VERSION 5.8 ;
BUSBITCHARS "[]" ;
DIVIDERCHAR "/" ;
UNITS
    DATABASE MICRONS 1000 ;
END UNITS

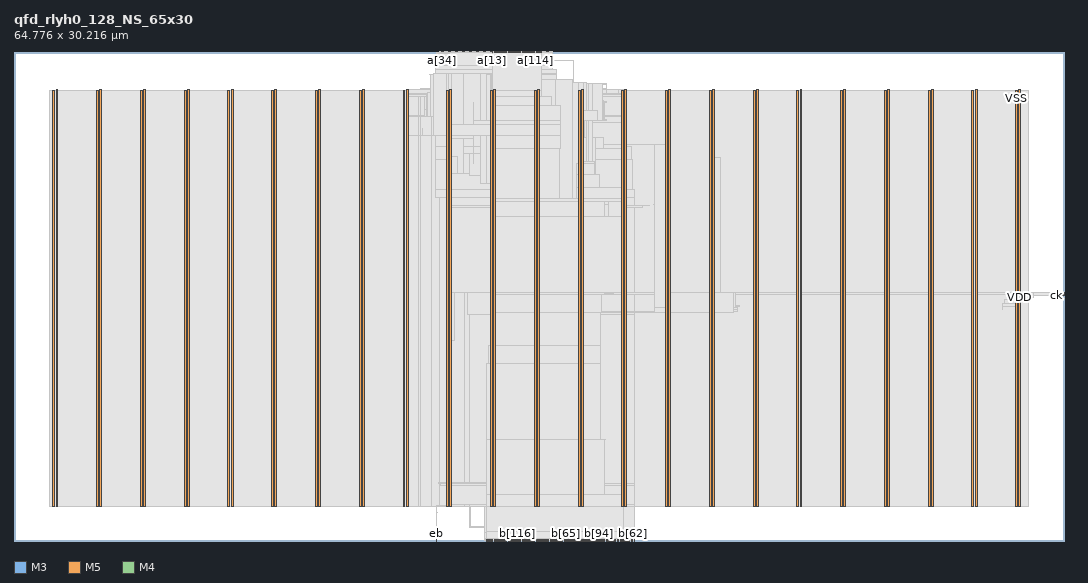
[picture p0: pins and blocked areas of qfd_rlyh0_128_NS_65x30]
MACRO qfd_rlyh0_128_NS_65x30
  FOREIGN qfd_rlyh0_128_NS_65x30 0 0 ;
  CLASS BLOCK ;
  SIZE 64.776 BY 30.216 ;
  PIN a[0]
    DIRECTION INPUT ;
    USE SIGNAL ;
    PORT
      LAYER M3 ;
        RECT  28.548 30.179 28.566 30.216 ;
    END
  END a[0]
  PIN a[100]
    DIRECTION INPUT ;
    USE SIGNAL ;
    PORT
      LAYER M3 ;
        RECT  31.14 30.179 31.158 30.216 ;
    END
  END a[100]
  PIN a[101]
    DIRECTION INPUT ;
    USE SIGNAL ;
    PORT
      LAYER M3 ;
        RECT  31.212 30.179 31.23 30.216 ;
    END
  END a[101]
  PIN a[102]
    DIRECTION INPUT ;
    USE SIGNAL ;
    PORT
      LAYER M3 ;
        RECT  31.284 30.179 31.302 30.216 ;
    END
  END a[102]
  PIN a[103]
    DIRECTION INPUT ;
    USE SIGNAL ;
    PORT
      LAYER M3 ;
        RECT  31.356 30.179 31.374 30.216 ;
    END
  END a[103]
  PIN a[104]
    DIRECTION INPUT ;
    USE SIGNAL ;
    PORT
      LAYER M3 ;
        RECT  31.428 30.179 31.446 30.216 ;
    END
  END a[104]
  PIN a[105]
    DIRECTION INPUT ;
    USE SIGNAL ;
    PORT
      LAYER M3 ;
        RECT  31.5 30.179 31.518 30.216 ;
    END
  END a[105]
  PIN a[106]
    DIRECTION INPUT ;
    USE SIGNAL ;
    PORT
      LAYER M3 ;
        RECT  31.572 30.179 31.59 30.216 ;
    END
  END a[106]
  PIN a[107]
    DIRECTION INPUT ;
    USE SIGNAL ;
    PORT
      LAYER M3 ;
        RECT  31.644 30.179 31.662 30.216 ;
    END
  END a[107]
  PIN a[108]
    DIRECTION INPUT ;
    USE SIGNAL ;
    PORT
      LAYER M3 ;
        RECT  31.716 30.179 31.734 30.216 ;
    END
  END a[108]
  PIN a[109]
    DIRECTION INPUT ;
    USE SIGNAL ;
    PORT
      LAYER M3 ;
        RECT  31.788 30.179 31.806 30.216 ;
    END
  END a[109]
  PIN a[10]
    DIRECTION INPUT ;
    USE SIGNAL ;
    PORT
      LAYER M3 ;
        RECT  29.268 30.179 29.286 30.216 ;
    END
  END a[10]
  PIN a[110]
    DIRECTION INPUT ;
    USE SIGNAL ;
    PORT
      LAYER M3 ;
        RECT  31.86 30.179 31.878 30.216 ;
    END
  END a[110]
  PIN a[111]
    DIRECTION INPUT ;
    USE SIGNAL ;
    PORT
      LAYER M3 ;
        RECT  31.932 30.179 31.95 30.216 ;
    END
  END a[111]
  PIN a[112]
    DIRECTION INPUT ;
    USE SIGNAL ;
    PORT
      LAYER M3 ;
        RECT  32.004 30.179 32.022 30.216 ;
    END
  END a[112]
  PIN a[113]
    DIRECTION INPUT ;
    USE SIGNAL ;
    PORT
      LAYER M3 ;
        RECT  32.076 30.179 32.094 30.216 ;
    END
  END a[113]
  PIN a[114]
    DIRECTION INPUT ;
    USE SIGNAL ;
    PORT
      LAYER M3 ;
        RECT  32.148 30.179 32.166 30.216 ;
    END
  END a[114]
  PIN a[115]
    DIRECTION INPUT ;
    USE SIGNAL ;
    PORT
      LAYER M3 ;
        RECT  32.22 30.179 32.238 30.216 ;
    END
  END a[115]
  PIN a[116]
    DIRECTION INPUT ;
    USE SIGNAL ;
    PORT
      LAYER M3 ;
        RECT  32.292 30.179 32.31 30.216 ;
    END
  END a[116]
  PIN a[117]
    DIRECTION INPUT ;
    USE SIGNAL ;
    PORT
      LAYER M3 ;
        RECT  32.364 30.179 32.382 30.216 ;
    END
  END a[117]
  PIN a[118]
    DIRECTION INPUT ;
    USE SIGNAL ;
    PORT
      LAYER M3 ;
        RECT  32.436 30.179 32.454 30.216 ;
    END
  END a[118]
  PIN a[119]
    DIRECTION INPUT ;
    USE SIGNAL ;
    PORT
      LAYER M3 ;
        RECT  32.508 30.179 32.526 30.216 ;
    END
  END a[119]
  PIN a[11]
    DIRECTION INPUT ;
    USE SIGNAL ;
    PORT
      LAYER M3 ;
        RECT  29.34 30.179 29.358 30.216 ;
    END
  END a[11]
  PIN a[120]
    DIRECTION INPUT ;
    USE SIGNAL ;
    PORT
      LAYER M3 ;
        RECT  32.58 30.179 32.598 30.216 ;
    END
  END a[120]
  PIN a[121]
    DIRECTION INPUT ;
    USE SIGNAL ;
    PORT
      LAYER M3 ;
        RECT  32.652 30.179 32.67 30.216 ;
    END
  END a[121]
  PIN a[122]
    DIRECTION INPUT ;
    USE SIGNAL ;
    PORT
      LAYER M3 ;
        RECT  32.724 30.179 32.742 30.216 ;
    END
  END a[122]
  PIN a[123]
    DIRECTION INPUT ;
    USE SIGNAL ;
    PORT
      LAYER M3 ;
        RECT  32.796 30.179 32.814 30.216 ;
    END
  END a[123]
  PIN a[124]
    DIRECTION INPUT ;
    USE SIGNAL ;
    PORT
      LAYER M3 ;
        RECT  32.868 30.179 32.886 30.216 ;
    END
  END a[124]
  PIN a[125]
    DIRECTION INPUT ;
    USE SIGNAL ;
    PORT
      LAYER M3 ;
        RECT  32.94 30.179 32.958 30.216 ;
    END
  END a[125]
  PIN a[126]
    DIRECTION INPUT ;
    USE SIGNAL ;
    PORT
      LAYER M3 ;
        RECT  33.012 30.179 33.03 30.216 ;
    END
  END a[126]
  PIN a[127]
    DIRECTION INPUT ;
    USE SIGNAL ;
    PORT
      LAYER M3 ;
        RECT  33.084 30.179 33.102 30.216 ;
    END
  END a[127]
  PIN a[12]
    DIRECTION INPUT ;
    USE SIGNAL ;
    PORT
      LAYER M3 ;
        RECT  29.412 30.179 29.43 30.216 ;
    END
  END a[12]
  PIN a[13]
    DIRECTION INPUT ;
    USE SIGNAL ;
    PORT
      LAYER M3 ;
        RECT  29.484 30.179 29.502 30.216 ;
    END
  END a[13]
  PIN a[14]
    DIRECTION INPUT ;
    USE SIGNAL ;
    PORT
      LAYER M3 ;
        RECT  29.556 30.179 29.574 30.216 ;
    END
  END a[14]
  PIN a[15]
    DIRECTION INPUT ;
    USE SIGNAL ;
    PORT
      LAYER M3 ;
        RECT  29.628 30.179 29.646 30.216 ;
    END
  END a[15]
  PIN a[16]
    DIRECTION INPUT ;
    USE SIGNAL ;
    PORT
      LAYER M3 ;
        RECT  29.7 30.179 29.718 30.216 ;
    END
  END a[16]
  PIN a[17]
    DIRECTION INPUT ;
    USE SIGNAL ;
    PORT
      LAYER M3 ;
        RECT  29.772 30.179 29.79 30.216 ;
    END
  END a[17]
  PIN a[18]
    DIRECTION INPUT ;
    USE SIGNAL ;
    PORT
      LAYER M3 ;
        RECT  29.844 30.179 29.862 30.216 ;
    END
  END a[18]
  PIN a[19]
    DIRECTION INPUT ;
    USE SIGNAL ;
    PORT
      LAYER M3 ;
        RECT  29.916 30.179 29.934 30.216 ;
    END
  END a[19]
  PIN a[1]
    DIRECTION INPUT ;
    USE SIGNAL ;
    PORT
      LAYER M3 ;
        RECT  28.62 30.179 28.638 30.216 ;
    END
  END a[1]
  PIN a[20]
    DIRECTION INPUT ;
    USE SIGNAL ;
    PORT
      LAYER M3 ;
        RECT  29.988 30.179 30.006 30.216 ;
    END
  END a[20]
  PIN a[21]
    DIRECTION INPUT ;
    USE SIGNAL ;
    PORT
      LAYER M3 ;
        RECT  30.06 30.179 30.078 30.216 ;
    END
  END a[21]
  PIN a[22]
    DIRECTION INPUT ;
    USE SIGNAL ;
    PORT
      LAYER M3 ;
        RECT  30.132 30.179 30.15 30.216 ;
    END
  END a[22]
  PIN a[23]
    DIRECTION INPUT ;
    USE SIGNAL ;
    PORT
      LAYER M3 ;
        RECT  30.204 30.179 30.222 30.216 ;
    END
  END a[23]
  PIN a[24]
    DIRECTION INPUT ;
    USE SIGNAL ;
    PORT
      LAYER M3 ;
        RECT  30.276 30.179 30.294 30.216 ;
    END
  END a[24]
  PIN a[25]
    DIRECTION INPUT ;
    USE SIGNAL ;
    PORT
      LAYER M3 ;
        RECT  30.348 30.179 30.366 30.216 ;
    END
  END a[25]
  PIN a[26]
    DIRECTION INPUT ;
    USE SIGNAL ;
    PORT
      LAYER M3 ;
        RECT  30.42 30.179 30.438 30.216 ;
    END
  END a[26]
  PIN a[27]
    DIRECTION INPUT ;
    USE SIGNAL ;
    PORT
      LAYER M3 ;
        RECT  30.492 30.179 30.51 30.216 ;
    END
  END a[27]
  PIN a[28]
    DIRECTION INPUT ;
    USE SIGNAL ;
    PORT
      LAYER M3 ;
        RECT  30.564 30.179 30.582 30.216 ;
    END
  END a[28]
  PIN a[29]
    DIRECTION INPUT ;
    USE SIGNAL ;
    PORT
      LAYER M3 ;
        RECT  30.636 30.179 30.654 30.216 ;
    END
  END a[29]
  PIN a[2]
    DIRECTION INPUT ;
    USE SIGNAL ;
    PORT
      LAYER M3 ;
        RECT  28.692 30.179 28.71 30.216 ;
    END
  END a[2]
  PIN a[30]
    DIRECTION INPUT ;
    USE SIGNAL ;
    PORT
      LAYER M3 ;
        RECT  30.708 30.179 30.726 30.216 ;
    END
  END a[30]
  PIN a[31]
    DIRECTION INPUT ;
    USE SIGNAL ;
    PORT
      LAYER M3 ;
        RECT  30.78 30.179 30.798 30.216 ;
    END
  END a[31]
  PIN a[32]
    DIRECTION INPUT ;
    USE SIGNAL ;
    PORT
      LAYER M3 ;
        RECT  26.244 30.179 26.262 30.216 ;
    END
  END a[32]
  PIN a[33]
    DIRECTION INPUT ;
    USE SIGNAL ;
    PORT
      LAYER M3 ;
        RECT  26.316 30.179 26.334 30.216 ;
    END
  END a[33]
  PIN a[34]
    DIRECTION INPUT ;
    USE SIGNAL ;
    PORT
      LAYER M3 ;
        RECT  26.388 30.179 26.406 30.216 ;
    END
  END a[34]
  PIN a[35]
    DIRECTION INPUT ;
    USE SIGNAL ;
    PORT
      LAYER M3 ;
        RECT  26.46 30.179 26.478 30.216 ;
    END
  END a[35]
  PIN a[36]
    DIRECTION INPUT ;
    USE SIGNAL ;
    PORT
      LAYER M3 ;
        RECT  26.532 30.179 26.55 30.216 ;
    END
  END a[36]
  PIN a[37]
    DIRECTION INPUT ;
    USE SIGNAL ;
    PORT
      LAYER M3 ;
        RECT  26.604 30.179 26.622 30.216 ;
    END
  END a[37]
  PIN a[38]
    DIRECTION INPUT ;
    USE SIGNAL ;
    PORT
      LAYER M3 ;
        RECT  26.676 30.179 26.694 30.216 ;
    END
  END a[38]
  PIN a[39]
    DIRECTION INPUT ;
    USE SIGNAL ;
    PORT
      LAYER M3 ;
        RECT  26.748 30.179 26.766 30.216 ;
    END
  END a[39]
  PIN a[3]
    DIRECTION INPUT ;
    USE SIGNAL ;
    PORT
      LAYER M3 ;
        RECT  28.764 30.179 28.782 30.216 ;
    END
  END a[3]
  PIN a[40]
    DIRECTION INPUT ;
    USE SIGNAL ;
    PORT
      LAYER M3 ;
        RECT  26.82 30.179 26.838 30.216 ;
    END
  END a[40]
  PIN a[41]
    DIRECTION INPUT ;
    USE SIGNAL ;
    PORT
      LAYER M3 ;
        RECT  26.892 30.179 26.91 30.216 ;
    END
  END a[41]
  PIN a[42]
    DIRECTION INPUT ;
    USE SIGNAL ;
    PORT
      LAYER M3 ;
        RECT  26.964 30.179 26.982 30.216 ;
    END
  END a[42]
  PIN a[43]
    DIRECTION INPUT ;
    USE SIGNAL ;
    PORT
      LAYER M3 ;
        RECT  27.036 30.179 27.054 30.216 ;
    END
  END a[43]
  PIN a[44]
    DIRECTION INPUT ;
    USE SIGNAL ;
    PORT
      LAYER M3 ;
        RECT  27.108 30.179 27.126 30.216 ;
    END
  END a[44]
  PIN a[45]
    DIRECTION INPUT ;
    USE SIGNAL ;
    PORT
      LAYER M3 ;
        RECT  27.18 30.179 27.198 30.216 ;
    END
  END a[45]
  PIN a[46]
    DIRECTION INPUT ;
    USE SIGNAL ;
    PORT
      LAYER M3 ;
        RECT  27.252 30.179 27.27 30.216 ;
    END
  END a[46]
  PIN a[47]
    DIRECTION INPUT ;
    USE SIGNAL ;
    PORT
      LAYER M3 ;
        RECT  27.324 30.179 27.342 30.216 ;
    END
  END a[47]
  PIN a[48]
    DIRECTION INPUT ;
    USE SIGNAL ;
    PORT
      LAYER M3 ;
        RECT  27.396 30.179 27.414 30.216 ;
    END
  END a[48]
  PIN a[49]
    DIRECTION INPUT ;
    USE SIGNAL ;
    PORT
      LAYER M3 ;
        RECT  27.468 30.179 27.486 30.216 ;
    END
  END a[49]
  PIN a[4]
    DIRECTION INPUT ;
    USE SIGNAL ;
    PORT
      LAYER M3 ;
        RECT  28.836 30.179 28.854 30.216 ;
    END
  END a[4]
  PIN a[50]
    DIRECTION INPUT ;
    USE SIGNAL ;
    PORT
      LAYER M3 ;
        RECT  27.54 30.179 27.558 30.216 ;
    END
  END a[50]
  PIN a[51]
    DIRECTION INPUT ;
    USE SIGNAL ;
    PORT
      LAYER M3 ;
        RECT  27.612 30.179 27.63 30.216 ;
    END
  END a[51]
  PIN a[52]
    DIRECTION INPUT ;
    USE SIGNAL ;
    PORT
      LAYER M3 ;
        RECT  27.684 30.179 27.702 30.216 ;
    END
  END a[52]
  PIN a[53]
    DIRECTION INPUT ;
    USE SIGNAL ;
    PORT
      LAYER M3 ;
        RECT  27.756 30.179 27.774 30.216 ;
    END
  END a[53]
  PIN a[54]
    DIRECTION INPUT ;
    USE SIGNAL ;
    PORT
      LAYER M3 ;
        RECT  27.828 30.179 27.846 30.216 ;
    END
  END a[54]
  PIN a[55]
    DIRECTION INPUT ;
    USE SIGNAL ;
    PORT
      LAYER M3 ;
        RECT  27.9 30.179 27.918 30.216 ;
    END
  END a[55]
  PIN a[56]
    DIRECTION INPUT ;
    USE SIGNAL ;
    PORT
      LAYER M3 ;
        RECT  27.972 30.179 27.99 30.216 ;
    END
  END a[56]
  PIN a[57]
    DIRECTION INPUT ;
    USE SIGNAL ;
    PORT
      LAYER M3 ;
        RECT  28.044 30.179 28.062 30.216 ;
    END
  END a[57]
  PIN a[58]
    DIRECTION INPUT ;
    USE SIGNAL ;
    PORT
      LAYER M3 ;
        RECT  28.116 30.179 28.134 30.216 ;
    END
  END a[58]
  PIN a[59]
    DIRECTION INPUT ;
    USE SIGNAL ;
    PORT
      LAYER M3 ;
        RECT  28.188 30.179 28.206 30.216 ;
    END
  END a[59]
  PIN a[5]
    DIRECTION INPUT ;
    USE SIGNAL ;
    PORT
      LAYER M3 ;
        RECT  28.908 30.179 28.926 30.216 ;
    END
  END a[5]
  PIN a[60]
    DIRECTION INPUT ;
    USE SIGNAL ;
    PORT
      LAYER M3 ;
        RECT  28.26 30.179 28.278 30.216 ;
    END
  END a[60]
  PIN a[61]
    DIRECTION INPUT ;
    USE SIGNAL ;
    PORT
      LAYER M3 ;
        RECT  28.332 30.179 28.35 30.216 ;
    END
  END a[61]
  PIN a[62]
    DIRECTION INPUT ;
    USE SIGNAL ;
    PORT
      LAYER M3 ;
        RECT  28.404 30.179 28.422 30.216 ;
    END
  END a[62]
  PIN a[63]
    DIRECTION INPUT ;
    USE SIGNAL ;
    PORT
      LAYER M3 ;
        RECT  28.476 30.179 28.494 30.216 ;
    END
  END a[63]
  PIN a[64]
    DIRECTION INPUT ;
    USE SIGNAL ;
    PORT
      LAYER M5 ;
        RECT  29.52 30.132 29.544 30.216 ;
    END
  END a[64]
  PIN a[65]
    DIRECTION INPUT ;
    USE SIGNAL ;
    PORT
      LAYER M5 ;
        RECT  29.616 30.132 29.64 30.216 ;
    END
  END a[65]
  PIN a[66]
    DIRECTION INPUT ;
    USE SIGNAL ;
    PORT
      LAYER M5 ;
        RECT  29.712 30.132 29.736 30.216 ;
    END
  END a[66]
  PIN a[67]
    DIRECTION INPUT ;
    USE SIGNAL ;
    PORT
      LAYER M5 ;
        RECT  29.808 30.132 29.832 30.216 ;
    END
  END a[67]
  PIN a[68]
    DIRECTION INPUT ;
    USE SIGNAL ;
    PORT
      LAYER M5 ;
        RECT  29.904 30.132 29.928 30.216 ;
    END
  END a[68]
  PIN a[69]
    DIRECTION INPUT ;
    USE SIGNAL ;
    PORT
      LAYER M5 ;
        RECT  30 30.132 30.024 30.216 ;
    END
  END a[69]
  PIN a[6]
    DIRECTION INPUT ;
    USE SIGNAL ;
    PORT
      LAYER M3 ;
        RECT  28.98 30.179 28.998 30.216 ;
    END
  END a[6]
  PIN a[70]
    DIRECTION INPUT ;
    USE SIGNAL ;
    PORT
      LAYER M5 ;
        RECT  30.096 30.132 30.12 30.216 ;
    END
  END a[70]
  PIN a[71]
    DIRECTION INPUT ;
    USE SIGNAL ;
    PORT
      LAYER M5 ;
        RECT  30.192 30.132 30.216 30.216 ;
    END
  END a[71]
  PIN a[72]
    DIRECTION INPUT ;
    USE SIGNAL ;
    PORT
      LAYER M5 ;
        RECT  30.288 30.132 30.312 30.216 ;
    END
  END a[72]
  PIN a[73]
    DIRECTION INPUT ;
    USE SIGNAL ;
    PORT
      LAYER M5 ;
        RECT  30.384 30.132 30.408 30.216 ;
    END
  END a[73]
  PIN a[74]
    DIRECTION INPUT ;
    USE SIGNAL ;
    PORT
      LAYER M5 ;
        RECT  30.48 30.132 30.504 30.216 ;
    END
  END a[74]
  PIN a[75]
    DIRECTION INPUT ;
    USE SIGNAL ;
    PORT
      LAYER M5 ;
        RECT  30.576 30.132 30.6 30.216 ;
    END
  END a[75]
  PIN a[76]
    DIRECTION INPUT ;
    USE SIGNAL ;
    PORT
      LAYER M5 ;
        RECT  30.672 30.132 30.696 30.216 ;
    END
  END a[76]
  PIN a[77]
    DIRECTION INPUT ;
    USE SIGNAL ;
    PORT
      LAYER M5 ;
        RECT  30.768 30.132 30.792 30.216 ;
    END
  END a[77]
  PIN a[78]
    DIRECTION INPUT ;
    USE SIGNAL ;
    PORT
      LAYER M5 ;
        RECT  30.864 30.132 30.888 30.216 ;
    END
  END a[78]
  PIN a[79]
    DIRECTION INPUT ;
    USE SIGNAL ;
    PORT
      LAYER M5 ;
        RECT  30.96 30.132 30.984 30.216 ;
    END
  END a[79]
  PIN a[7]
    DIRECTION INPUT ;
    USE SIGNAL ;
    PORT
      LAYER M3 ;
        RECT  29.052 30.179 29.07 30.216 ;
    END
  END a[7]
  PIN a[80]
    DIRECTION INPUT ;
    USE SIGNAL ;
    PORT
      LAYER M5 ;
        RECT  31.056 30.132 31.08 30.216 ;
    END
  END a[80]
  PIN a[81]
    DIRECTION INPUT ;
    USE SIGNAL ;
    PORT
      LAYER M5 ;
        RECT  31.152 30.132 31.176 30.216 ;
    END
  END a[81]
  PIN a[82]
    DIRECTION INPUT ;
    USE SIGNAL ;
    PORT
      LAYER M5 ;
        RECT  31.248 30.132 31.272 30.216 ;
    END
  END a[82]
  PIN a[83]
    DIRECTION INPUT ;
    USE SIGNAL ;
    PORT
      LAYER M5 ;
        RECT  31.344 30.132 31.368 30.216 ;
    END
  END a[83]
  PIN a[84]
    DIRECTION INPUT ;
    USE SIGNAL ;
    PORT
      LAYER M5 ;
        RECT  31.44 30.132 31.464 30.216 ;
    END
  END a[84]
  PIN a[85]
    DIRECTION INPUT ;
    USE SIGNAL ;
    PORT
      LAYER M5 ;
        RECT  31.536 30.132 31.56 30.216 ;
    END
  END a[85]
  PIN a[86]
    DIRECTION INPUT ;
    USE SIGNAL ;
    PORT
      LAYER M5 ;
        RECT  31.632 30.132 31.656 30.216 ;
    END
  END a[86]
  PIN a[87]
    DIRECTION INPUT ;
    USE SIGNAL ;
    PORT
      LAYER M5 ;
        RECT  31.728 30.132 31.752 30.216 ;
    END
  END a[87]
  PIN a[88]
    DIRECTION INPUT ;
    USE SIGNAL ;
    PORT
      LAYER M5 ;
        RECT  31.824 30.132 31.848 30.216 ;
    END
  END a[88]
  PIN a[89]
    DIRECTION INPUT ;
    USE SIGNAL ;
    PORT
      LAYER M5 ;
        RECT  31.92 30.132 31.944 30.216 ;
    END
  END a[89]
  PIN a[8]
    DIRECTION INPUT ;
    USE SIGNAL ;
    PORT
      LAYER M3 ;
        RECT  29.124 30.179 29.142 30.216 ;
    END
  END a[8]
  PIN a[90]
    DIRECTION INPUT ;
    USE SIGNAL ;
    PORT
      LAYER M5 ;
        RECT  32.016 30.132 32.04 30.216 ;
    END
  END a[90]
  PIN a[91]
    DIRECTION INPUT ;
    USE SIGNAL ;
    PORT
      LAYER M5 ;
        RECT  32.112 30.132 32.136 30.216 ;
    END
  END a[91]
  PIN a[92]
    DIRECTION INPUT ;
    USE SIGNAL ;
    PORT
      LAYER M5 ;
        RECT  32.208 30.132 32.232 30.216 ;
    END
  END a[92]
  PIN a[93]
    DIRECTION INPUT ;
    USE SIGNAL ;
    PORT
      LAYER M5 ;
        RECT  32.304 30.132 32.328 30.216 ;
    END
  END a[93]
  PIN a[94]
    DIRECTION INPUT ;
    USE SIGNAL ;
    PORT
      LAYER M5 ;
        RECT  32.4 30.132 32.424 30.216 ;
    END
  END a[94]
  PIN a[95]
    DIRECTION INPUT ;
    USE SIGNAL ;
    PORT
      LAYER M5 ;
        RECT  32.496 30.132 32.52 30.216 ;
    END
  END a[95]
  PIN a[96]
    DIRECTION INPUT ;
    USE SIGNAL ;
    PORT
      LAYER M3 ;
        RECT  30.852 30.179 30.87 30.216 ;
    END
  END a[96]
  PIN a[97]
    DIRECTION INPUT ;
    USE SIGNAL ;
    PORT
      LAYER M3 ;
        RECT  30.924 30.179 30.942 30.216 ;
    END
  END a[97]
  PIN a[98]
    DIRECTION INPUT ;
    USE SIGNAL ;
    PORT
      LAYER M3 ;
        RECT  30.996 30.179 31.014 30.216 ;
    END
  END a[98]
  PIN a[99]
    DIRECTION INPUT ;
    USE SIGNAL ;
    PORT
      LAYER M3 ;
        RECT  31.068 30.179 31.086 30.216 ;
    END
  END a[99]
  PIN a[9]
    DIRECTION INPUT ;
    USE SIGNAL ;
    PORT
      LAYER M3 ;
        RECT  29.196 30.179 29.214 30.216 ;
    END
  END a[9]
  PIN b[0]
    DIRECTION OUTPUT ;
    USE SIGNAL ;
    PORT
      LAYER M5 ;
        RECT  32.208 0 32.232 0.084 ;
    END
  END b[0]
  PIN b[100]
    DIRECTION OUTPUT ;
    USE SIGNAL ;
    PORT
      LAYER M5 ;
        RECT  29.52 0 29.544 0.084 ;
    END
  END b[100]
  PIN b[101]
    DIRECTION OUTPUT ;
    USE SIGNAL ;
    PORT
      LAYER M5 ;
        RECT  29.616 0 29.64 0.084 ;
    END
  END b[101]
  PIN b[102]
    DIRECTION OUTPUT ;
    USE SIGNAL ;
    PORT
      LAYER M5 ;
        RECT  29.712 0 29.736 0.084 ;
    END
  END b[102]
  PIN b[103]
    DIRECTION OUTPUT ;
    USE SIGNAL ;
    PORT
      LAYER M5 ;
        RECT  29.808 0 29.832 0.084 ;
    END
  END b[103]
  PIN b[104]
    DIRECTION OUTPUT ;
    USE SIGNAL ;
    PORT
      LAYER M5 ;
        RECT  29.904 0 29.928 0.084 ;
    END
  END b[104]
  PIN b[105]
    DIRECTION OUTPUT ;
    USE SIGNAL ;
    PORT
      LAYER M5 ;
        RECT  30 0 30.024 0.084 ;
    END
  END b[105]
  PIN b[106]
    DIRECTION OUTPUT ;
    USE SIGNAL ;
    PORT
      LAYER M5 ;
        RECT  30.096 0 30.12 0.084 ;
    END
  END b[106]
  PIN b[107]
    DIRECTION OUTPUT ;
    USE SIGNAL ;
    PORT
      LAYER M5 ;
        RECT  30.192 0 30.216 0.084 ;
    END
  END b[107]
  PIN b[108]
    DIRECTION OUTPUT ;
    USE SIGNAL ;
    PORT
      LAYER M5 ;
        RECT  30.288 0 30.312 0.084 ;
    END
  END b[108]
  PIN b[109]
    DIRECTION OUTPUT ;
    USE SIGNAL ;
    PORT
      LAYER M5 ;
        RECT  30.384 0 30.408 0.084 ;
    END
  END b[109]
  PIN b[10]
    DIRECTION OUTPUT ;
    USE SIGNAL ;
    PORT
      LAYER M5 ;
        RECT  33.168 0 33.192 0.084 ;
    END
  END b[10]
  PIN b[110]
    DIRECTION OUTPUT ;
    USE SIGNAL ;
    PORT
      LAYER M5 ;
        RECT  30.48 0 30.504 0.084 ;
    END
  END b[110]
  PIN b[111]
    DIRECTION OUTPUT ;
    USE SIGNAL ;
    PORT
      LAYER M5 ;
        RECT  30.576 0 30.6 0.084 ;
    END
  END b[111]
  PIN b[112]
    DIRECTION OUTPUT ;
    USE SIGNAL ;
    PORT
      LAYER M5 ;
        RECT  30.672 0 30.696 0.084 ;
    END
  END b[112]
  PIN b[113]
    DIRECTION OUTPUT ;
    USE SIGNAL ;
    PORT
      LAYER M5 ;
        RECT  30.768 0 30.792 0.084 ;
    END
  END b[113]
  PIN b[114]
    DIRECTION OUTPUT ;
    USE SIGNAL ;
    PORT
      LAYER M5 ;
        RECT  30.864 0 30.888 0.084 ;
    END
  END b[114]
  PIN b[115]
    DIRECTION OUTPUT ;
    USE SIGNAL ;
    PORT
      LAYER M5 ;
        RECT  30.96 0 30.984 0.084 ;
    END
  END b[115]
  PIN b[116]
    DIRECTION OUTPUT ;
    USE SIGNAL ;
    PORT
      LAYER M5 ;
        RECT  31.056 0 31.08 0.084 ;
    END
  END b[116]
  PIN b[117]
    DIRECTION OUTPUT ;
    USE SIGNAL ;
    PORT
      LAYER M5 ;
        RECT  31.152 0 31.176 0.084 ;
    END
  END b[117]
  PIN b[118]
    DIRECTION OUTPUT ;
    USE SIGNAL ;
    PORT
      LAYER M5 ;
        RECT  31.248 0 31.272 0.084 ;
    END
  END b[118]
  PIN b[119]
    DIRECTION OUTPUT ;
    USE SIGNAL ;
    PORT
      LAYER M5 ;
        RECT  31.344 0 31.368 0.084 ;
    END
  END b[119]
  PIN b[11]
    DIRECTION OUTPUT ;
    USE SIGNAL ;
    PORT
      LAYER M5 ;
        RECT  33.264 0 33.288 0.084 ;
    END
  END b[11]
  PIN b[120]
    DIRECTION OUTPUT ;
    USE SIGNAL ;
    PORT
      LAYER M5 ;
        RECT  31.44 0 31.464 0.084 ;
    END
  END b[120]
  PIN b[121]
    DIRECTION OUTPUT ;
    USE SIGNAL ;
    PORT
      LAYER M5 ;
        RECT  31.536 0 31.56 0.084 ;
    END
  END b[121]
  PIN b[122]
    DIRECTION OUTPUT ;
    USE SIGNAL ;
    PORT
      LAYER M5 ;
        RECT  31.632 0 31.656 0.084 ;
    END
  END b[122]
  PIN b[123]
    DIRECTION OUTPUT ;
    USE SIGNAL ;
    PORT
      LAYER M5 ;
        RECT  31.728 0 31.752 0.084 ;
    END
  END b[123]
  PIN b[124]
    DIRECTION OUTPUT ;
    USE SIGNAL ;
    PORT
      LAYER M5 ;
        RECT  31.824 0 31.848 0.084 ;
    END
  END b[124]
  PIN b[125]
    DIRECTION OUTPUT ;
    USE SIGNAL ;
    PORT
      LAYER M5 ;
        RECT  31.92 0 31.944 0.084 ;
    END
  END b[125]
  PIN b[126]
    DIRECTION OUTPUT ;
    USE SIGNAL ;
    PORT
      LAYER M5 ;
        RECT  32.016 0 32.04 0.084 ;
    END
  END b[126]
  PIN b[127]
    DIRECTION OUTPUT ;
    USE SIGNAL ;
    PORT
      LAYER M5 ;
        RECT  32.112 0 32.136 0.084 ;
    END
  END b[127]
  PIN b[12]
    DIRECTION OUTPUT ;
    USE SIGNAL ;
    PORT
      LAYER M5 ;
        RECT  33.36 0 33.384 0.084 ;
    END
  END b[12]
  PIN b[13]
    DIRECTION OUTPUT ;
    USE SIGNAL ;
    PORT
      LAYER M5 ;
        RECT  33.456 0 33.48 0.084 ;
    END
  END b[13]
  PIN b[14]
    DIRECTION OUTPUT ;
    USE SIGNAL ;
    PORT
      LAYER M5 ;
        RECT  33.552 0 33.576 0.084 ;
    END
  END b[14]
  PIN b[15]
    DIRECTION OUTPUT ;
    USE SIGNAL ;
    PORT
      LAYER M5 ;
        RECT  33.648 0 33.672 0.084 ;
    END
  END b[15]
  PIN b[16]
    DIRECTION OUTPUT ;
    USE SIGNAL ;
    PORT
      LAYER M5 ;
        RECT  33.744 0 33.768 0.084 ;
    END
  END b[16]
  PIN b[17]
    DIRECTION OUTPUT ;
    USE SIGNAL ;
    PORT
      LAYER M5 ;
        RECT  33.84 0 33.864 0.084 ;
    END
  END b[17]
  PIN b[18]
    DIRECTION OUTPUT ;
    USE SIGNAL ;
    PORT
      LAYER M5 ;
        RECT  33.936 0 33.96 0.084 ;
    END
  END b[18]
  PIN b[19]
    DIRECTION OUTPUT ;
    USE SIGNAL ;
    PORT
      LAYER M5 ;
        RECT  34.032 0 34.056 0.084 ;
    END
  END b[19]
  PIN b[1]
    DIRECTION OUTPUT ;
    USE SIGNAL ;
    PORT
      LAYER M5 ;
        RECT  32.304 0 32.328 0.084 ;
    END
  END b[1]
  PIN b[20]
    DIRECTION OUTPUT ;
    USE SIGNAL ;
    PORT
      LAYER M5 ;
        RECT  34.128 0 34.152 0.084 ;
    END
  END b[20]
  PIN b[21]
    DIRECTION OUTPUT ;
    USE SIGNAL ;
    PORT
      LAYER M5 ;
        RECT  34.224 0 34.248 0.084 ;
    END
  END b[21]
  PIN b[22]
    DIRECTION OUTPUT ;
    USE SIGNAL ;
    PORT
      LAYER M5 ;
        RECT  34.32 0 34.344 0.084 ;
    END
  END b[22]
  PIN b[23]
    DIRECTION OUTPUT ;
    USE SIGNAL ;
    PORT
      LAYER M5 ;
        RECT  34.416 0 34.44 0.084 ;
    END
  END b[23]
  PIN b[24]
    DIRECTION OUTPUT ;
    USE SIGNAL ;
    PORT
      LAYER M5 ;
        RECT  34.512 0 34.536 0.084 ;
    END
  END b[24]
  PIN b[25]
    DIRECTION OUTPUT ;
    USE SIGNAL ;
    PORT
      LAYER M5 ;
        RECT  34.608 0 34.632 0.084 ;
    END
  END b[25]
  PIN b[26]
    DIRECTION OUTPUT ;
    USE SIGNAL ;
    PORT
      LAYER M5 ;
        RECT  34.704 0 34.728 0.084 ;
    END
  END b[26]
  PIN b[27]
    DIRECTION OUTPUT ;
    USE SIGNAL ;
    PORT
      LAYER M5 ;
        RECT  34.8 0 34.824 0.084 ;
    END
  END b[27]
  PIN b[28]
    DIRECTION OUTPUT ;
    USE SIGNAL ;
    PORT
      LAYER M5 ;
        RECT  34.896 0 34.92 0.084 ;
    END
  END b[28]
  PIN b[29]
    DIRECTION OUTPUT ;
    USE SIGNAL ;
    PORT
      LAYER M5 ;
        RECT  34.992 0 35.016 0.084 ;
    END
  END b[29]
  PIN b[2]
    DIRECTION OUTPUT ;
    USE SIGNAL ;
    PORT
      LAYER M5 ;
        RECT  32.4 0 32.424 0.084 ;
    END
  END b[2]
  PIN b[30]
    DIRECTION OUTPUT ;
    USE SIGNAL ;
    PORT
      LAYER M5 ;
        RECT  35.088 0 35.112 0.084 ;
    END
  END b[30]
  PIN b[31]
    DIRECTION OUTPUT ;
    USE SIGNAL ;
    PORT
      LAYER M5 ;
        RECT  35.184 0 35.208 0.084 ;
    END
  END b[31]
  PIN b[32]
    DIRECTION OUTPUT ;
    USE SIGNAL ;
    PORT
      LAYER M5 ;
        RECT  35.28 0 35.304 0.084 ;
    END
  END b[32]
  PIN b[33]
    DIRECTION OUTPUT ;
    USE SIGNAL ;
    PORT
      LAYER M5 ;
        RECT  35.376 0 35.4 0.084 ;
    END
  END b[33]
  PIN b[34]
    DIRECTION OUTPUT ;
    USE SIGNAL ;
    PORT
      LAYER M5 ;
        RECT  35.472 0 35.496 0.084 ;
    END
  END b[34]
  PIN b[35]
    DIRECTION OUTPUT ;
    USE SIGNAL ;
    PORT
      LAYER M5 ;
        RECT  35.568 0 35.592 0.084 ;
    END
  END b[35]
  PIN b[36]
    DIRECTION OUTPUT ;
    USE SIGNAL ;
    PORT
      LAYER M5 ;
        RECT  35.664 0 35.688 0.084 ;
    END
  END b[36]
  PIN b[37]
    DIRECTION OUTPUT ;
    USE SIGNAL ;
    PORT
      LAYER M5 ;
        RECT  35.76 0 35.784 0.084 ;
    END
  END b[37]
  PIN b[38]
    DIRECTION OUTPUT ;
    USE SIGNAL ;
    PORT
      LAYER M5 ;
        RECT  35.856 0 35.88 0.084 ;
    END
  END b[38]
  PIN b[39]
    DIRECTION OUTPUT ;
    USE SIGNAL ;
    PORT
      LAYER M5 ;
        RECT  35.952 0 35.976 0.084 ;
    END
  END b[39]
  PIN b[3]
    DIRECTION OUTPUT ;
    USE SIGNAL ;
    PORT
      LAYER M5 ;
        RECT  32.496 0 32.52 0.084 ;
    END
  END b[3]
  PIN b[40]
    DIRECTION OUTPUT ;
    USE SIGNAL ;
    PORT
      LAYER M5 ;
        RECT  36.048 0 36.072 0.084 ;
    END
  END b[40]
  PIN b[41]
    DIRECTION OUTPUT ;
    USE SIGNAL ;
    PORT
      LAYER M5 ;
        RECT  36.144 0 36.168 0.084 ;
    END
  END b[41]
  PIN b[42]
    DIRECTION OUTPUT ;
    USE SIGNAL ;
    PORT
      LAYER M5 ;
        RECT  36.24 0 36.264 0.084 ;
    END
  END b[42]
  PIN b[43]
    DIRECTION OUTPUT ;
    USE SIGNAL ;
    PORT
      LAYER M5 ;
        RECT  36.336 0 36.36 0.084 ;
    END
  END b[43]
  PIN b[44]
    DIRECTION OUTPUT ;
    USE SIGNAL ;
    PORT
      LAYER M5 ;
        RECT  36.432 0 36.456 0.084 ;
    END
  END b[44]
  PIN b[45]
    DIRECTION OUTPUT ;
    USE SIGNAL ;
    PORT
      LAYER M5 ;
        RECT  36.528 0 36.552 0.084 ;
    END
  END b[45]
  PIN b[46]
    DIRECTION OUTPUT ;
    USE SIGNAL ;
    PORT
      LAYER M5 ;
        RECT  36.624 0 36.648 0.084 ;
    END
  END b[46]
  PIN b[47]
    DIRECTION OUTPUT ;
    USE SIGNAL ;
    PORT
      LAYER M5 ;
        RECT  36.72 0 36.744 0.084 ;
    END
  END b[47]
  PIN b[48]
    DIRECTION OUTPUT ;
    USE SIGNAL ;
    PORT
      LAYER M5 ;
        RECT  36.816 0 36.84 0.084 ;
    END
  END b[48]
  PIN b[49]
    DIRECTION OUTPUT ;
    USE SIGNAL ;
    PORT
      LAYER M5 ;
        RECT  36.912 0 36.936 0.084 ;
    END
  END b[49]
  PIN b[4]
    DIRECTION OUTPUT ;
    USE SIGNAL ;
    PORT
      LAYER M5 ;
        RECT  32.592 0 32.616 0.084 ;
    END
  END b[4]
  PIN b[50]
    DIRECTION OUTPUT ;
    USE SIGNAL ;
    PORT
      LAYER M5 ;
        RECT  37.008 0 37.032 0.084 ;
    END
  END b[50]
  PIN b[51]
    DIRECTION OUTPUT ;
    USE SIGNAL ;
    PORT
      LAYER M5 ;
        RECT  37.104 0 37.128 0.084 ;
    END
  END b[51]
  PIN b[52]
    DIRECTION OUTPUT ;
    USE SIGNAL ;
    PORT
      LAYER M5 ;
        RECT  37.2 0 37.224 0.084 ;
    END
  END b[52]
  PIN b[53]
    DIRECTION OUTPUT ;
    USE SIGNAL ;
    PORT
      LAYER M5 ;
        RECT  37.296 0 37.32 0.084 ;
    END
  END b[53]
  PIN b[54]
    DIRECTION OUTPUT ;
    USE SIGNAL ;
    PORT
      LAYER M5 ;
        RECT  37.392 0 37.416 0.084 ;
    END
  END b[54]
  PIN b[55]
    DIRECTION OUTPUT ;
    USE SIGNAL ;
    PORT
      LAYER M5 ;
        RECT  37.488 0 37.512 0.084 ;
    END
  END b[55]
  PIN b[56]
    DIRECTION OUTPUT ;
    USE SIGNAL ;
    PORT
      LAYER M5 ;
        RECT  37.584 0 37.608 0.084 ;
    END
  END b[56]
  PIN b[57]
    DIRECTION OUTPUT ;
    USE SIGNAL ;
    PORT
      LAYER M5 ;
        RECT  37.68 0 37.704 0.084 ;
    END
  END b[57]
  PIN b[58]
    DIRECTION OUTPUT ;
    USE SIGNAL ;
    PORT
      LAYER M5 ;
        RECT  37.776 0 37.8 0.084 ;
    END
  END b[58]
  PIN b[59]
    DIRECTION OUTPUT ;
    USE SIGNAL ;
    PORT
      LAYER M5 ;
        RECT  37.872 0 37.896 0.084 ;
    END
  END b[59]
  PIN b[5]
    DIRECTION OUTPUT ;
    USE SIGNAL ;
    PORT
      LAYER M5 ;
        RECT  32.688 0 32.712 0.084 ;
    END
  END b[5]
  PIN b[60]
    DIRECTION OUTPUT ;
    USE SIGNAL ;
    PORT
      LAYER M5 ;
        RECT  37.968 0 37.992 0.084 ;
    END
  END b[60]
  PIN b[61]
    DIRECTION OUTPUT ;
    USE SIGNAL ;
    PORT
      LAYER M5 ;
        RECT  38.064 0 38.088 0.084 ;
    END
  END b[61]
  PIN b[62]
    DIRECTION OUTPUT ;
    USE SIGNAL ;
    PORT
      LAYER M5 ;
        RECT  38.16 0 38.184 0.084 ;
    END
  END b[62]
  PIN b[63]
    DIRECTION OUTPUT ;
    USE SIGNAL ;
    PORT
      LAYER M5 ;
        RECT  38.256 0 38.28 0.084 ;
    END
  END b[63]
  PIN b[64]
    DIRECTION OUTPUT ;
    USE SIGNAL ;
    PORT
      LAYER M3 ;
        RECT  33.948 0 33.966 0.037 ;
    END
  END b[64]
  PIN b[65]
    DIRECTION OUTPUT ;
    USE SIGNAL ;
    PORT
      LAYER M3 ;
        RECT  34.02 0 34.038 0.037 ;
    END
  END b[65]
  PIN b[66]
    DIRECTION OUTPUT ;
    USE SIGNAL ;
    PORT
      LAYER M3 ;
        RECT  34.092 0 34.11 0.037 ;
    END
  END b[66]
  PIN b[67]
    DIRECTION OUTPUT ;
    USE SIGNAL ;
    PORT
      LAYER M3 ;
        RECT  34.164 0 34.182 0.037 ;
    END
  END b[67]
  PIN b[68]
    DIRECTION OUTPUT ;
    USE SIGNAL ;
    PORT
      LAYER M3 ;
        RECT  34.236 0 34.254 0.037 ;
    END
  END b[68]
  PIN b[69]
    DIRECTION OUTPUT ;
    USE SIGNAL ;
    PORT
      LAYER M3 ;
        RECT  34.308 0 34.326 0.037 ;
    END
  END b[69]
  PIN b[6]
    DIRECTION OUTPUT ;
    USE SIGNAL ;
    PORT
      LAYER M5 ;
        RECT  32.784 0 32.808 0.084 ;
    END
  END b[6]
  PIN b[70]
    DIRECTION OUTPUT ;
    USE SIGNAL ;
    PORT
      LAYER M3 ;
        RECT  34.38 0 34.398 0.037 ;
    END
  END b[70]
  PIN b[71]
    DIRECTION OUTPUT ;
    USE SIGNAL ;
    PORT
      LAYER M3 ;
        RECT  34.452 0 34.47 0.037 ;
    END
  END b[71]
  PIN b[72]
    DIRECTION OUTPUT ;
    USE SIGNAL ;
    PORT
      LAYER M3 ;
        RECT  34.524 0 34.542 0.037 ;
    END
  END b[72]
  PIN b[73]
    DIRECTION OUTPUT ;
    USE SIGNAL ;
    PORT
      LAYER M3 ;
        RECT  34.596 0 34.614 0.037 ;
    END
  END b[73]
  PIN b[74]
    DIRECTION OUTPUT ;
    USE SIGNAL ;
    PORT
      LAYER M3 ;
        RECT  34.668 0 34.686 0.037 ;
    END
  END b[74]
  PIN b[75]
    DIRECTION OUTPUT ;
    USE SIGNAL ;
    PORT
      LAYER M3 ;
        RECT  34.74 0 34.758 0.037 ;
    END
  END b[75]
  PIN b[76]
    DIRECTION OUTPUT ;
    USE SIGNAL ;
    PORT
      LAYER M3 ;
        RECT  34.812 0 34.83 0.037 ;
    END
  END b[76]
  PIN b[77]
    DIRECTION OUTPUT ;
    USE SIGNAL ;
    PORT
      LAYER M3 ;
        RECT  34.884 0 34.902 0.037 ;
    END
  END b[77]
  PIN b[78]
    DIRECTION OUTPUT ;
    USE SIGNAL ;
    PORT
      LAYER M3 ;
        RECT  34.956 0 34.974 0.037 ;
    END
  END b[78]
  PIN b[79]
    DIRECTION OUTPUT ;
    USE SIGNAL ;
    PORT
      LAYER M3 ;
        RECT  35.028 0 35.046 0.037 ;
    END
  END b[79]
  PIN b[7]
    DIRECTION OUTPUT ;
    USE SIGNAL ;
    PORT
      LAYER M5 ;
        RECT  32.88 0 32.904 0.084 ;
    END
  END b[7]
  PIN b[80]
    DIRECTION OUTPUT ;
    USE SIGNAL ;
    PORT
      LAYER M3 ;
        RECT  35.1 0 35.118 0.037 ;
    END
  END b[80]
  PIN b[81]
    DIRECTION OUTPUT ;
    USE SIGNAL ;
    PORT
      LAYER M3 ;
        RECT  35.172 0 35.19 0.037 ;
    END
  END b[81]
  PIN b[82]
    DIRECTION OUTPUT ;
    USE SIGNAL ;
    PORT
      LAYER M3 ;
        RECT  35.244 0 35.262 0.037 ;
    END
  END b[82]
  PIN b[83]
    DIRECTION OUTPUT ;
    USE SIGNAL ;
    PORT
      LAYER M3 ;
        RECT  35.316 0 35.334 0.037 ;
    END
  END b[83]
  PIN b[84]
    DIRECTION OUTPUT ;
    USE SIGNAL ;
    PORT
      LAYER M3 ;
        RECT  35.388 0 35.406 0.037 ;
    END
  END b[84]
  PIN b[85]
    DIRECTION OUTPUT ;
    USE SIGNAL ;
    PORT
      LAYER M3 ;
        RECT  35.46 0 35.478 0.037 ;
    END
  END b[85]
  PIN b[86]
    DIRECTION OUTPUT ;
    USE SIGNAL ;
    PORT
      LAYER M3 ;
        RECT  35.532 0 35.55 0.037 ;
    END
  END b[86]
  PIN b[87]
    DIRECTION OUTPUT ;
    USE SIGNAL ;
    PORT
      LAYER M3 ;
        RECT  35.604 0 35.622 0.037 ;
    END
  END b[87]
  PIN b[88]
    DIRECTION OUTPUT ;
    USE SIGNAL ;
    PORT
      LAYER M3 ;
        RECT  35.676 0 35.694 0.037 ;
    END
  END b[88]
  PIN b[89]
    DIRECTION OUTPUT ;
    USE SIGNAL ;
    PORT
      LAYER M3 ;
        RECT  35.748 0 35.766 0.037 ;
    END
  END b[89]
  PIN b[8]
    DIRECTION OUTPUT ;
    USE SIGNAL ;
    PORT
      LAYER M5 ;
        RECT  32.976 0 33 0.084 ;
    END
  END b[8]
  PIN b[90]
    DIRECTION OUTPUT ;
    USE SIGNAL ;
    PORT
      LAYER M3 ;
        RECT  35.82 0 35.838 0.037 ;
    END
  END b[90]
  PIN b[91]
    DIRECTION OUTPUT ;
    USE SIGNAL ;
    PORT
      LAYER M3 ;
        RECT  35.892 0 35.91 0.037 ;
    END
  END b[91]
  PIN b[92]
    DIRECTION OUTPUT ;
    USE SIGNAL ;
    PORT
      LAYER M3 ;
        RECT  35.964 0 35.982 0.037 ;
    END
  END b[92]
  PIN b[93]
    DIRECTION OUTPUT ;
    USE SIGNAL ;
    PORT
      LAYER M3 ;
        RECT  36.036 0 36.054 0.037 ;
    END
  END b[93]
  PIN b[94]
    DIRECTION OUTPUT ;
    USE SIGNAL ;
    PORT
      LAYER M3 ;
        RECT  36.108 0 36.126 0.037 ;
    END
  END b[94]
  PIN b[95]
    DIRECTION OUTPUT ;
    USE SIGNAL ;
    PORT
      LAYER M3 ;
        RECT  36.18 0 36.198 0.037 ;
    END
  END b[95]
  PIN b[96]
    DIRECTION OUTPUT ;
    USE SIGNAL ;
    PORT
      LAYER M5 ;
        RECT  29.136 0 29.16 0.084 ;
    END
  END b[96]
  PIN b[97]
    DIRECTION OUTPUT ;
    USE SIGNAL ;
    PORT
      LAYER M5 ;
        RECT  29.232 0 29.256 0.084 ;
    END
  END b[97]
  PIN b[98]
    DIRECTION OUTPUT ;
    USE SIGNAL ;
    PORT
      LAYER M5 ;
        RECT  29.328 0 29.352 0.084 ;
    END
  END b[98]
  PIN b[99]
    DIRECTION OUTPUT ;
    USE SIGNAL ;
    PORT
      LAYER M5 ;
        RECT  29.424 0 29.448 0.084 ;
    END
  END b[99]
  PIN b[9]
    DIRECTION OUTPUT ;
    USE SIGNAL ;
    PORT
      LAYER M5 ;
        RECT  33.072 0 33.096 0.084 ;
    END
  END b[9]
  PIN ck
    DIRECTION INPUT ;
    USE SIGNAL ;
    PORT
      LAYER M4 ;
        RECT  64.692 15.12 64.776 15.144 ;
    END
  END ck
  PIN ck_o
    DIRECTION OUTPUT ;
    USE SIGNAL ;
    PORT
      LAYER M4 ;
        RECT  64.692 15.216 64.776 15.24 ;
    END
  END ck_o
  PIN eb
    DIRECTION OUTPUT ;
    USE SIGNAL ;
    PORT
      LAYER M5 ;
        RECT  26.064 0 26.088 0.084 ;
    END
  END eb
  PIN en
    DIRECTION INPUT ;
    USE SIGNAL ;
    PORT
      LAYER M4 ;
        RECT  64.692 15.312 64.776 15.336 ;
    END
  END en
  PIN VDD
    DIRECTION INOUT ;
    USE POWER ;
    PORT
      LAYER M5 ;
        RECT  61.992 2.151 62.112 27.833 ;
        RECT  59.292 2.151 59.412 27.833 ;
        RECT  56.592 2.151 56.712 27.833 ;
        RECT  53.892 2.151 54.012 27.833 ;
        RECT  51.192 2.151 51.312 27.833 ;
        RECT  48.492 2.151 48.612 27.833 ;
        RECT  45.792 2.151 45.912 27.833 ;
        RECT  43.092 2.151 43.212 27.833 ;
        RECT  40.392 2.151 40.512 27.833 ;
        RECT  37.692 2.151 37.812 27.833 ;
        RECT  34.992 2.151 35.112 27.833 ;
        RECT  32.292 2.151 32.412 27.833 ;
        RECT  29.592 2.151 29.712 27.833 ;
        RECT  26.892 2.151 27.012 27.833 ;
        RECT  24.192 2.151 24.312 27.833 ;
        RECT  21.492 2.151 21.612 27.833 ;
        RECT  18.792 2.151 18.912 27.833 ;
        RECT  16.092 2.151 16.212 27.833 ;
        RECT  13.392 2.151 13.512 27.833 ;
        RECT  10.692 2.151 10.812 27.833 ;
        RECT  7.992 2.151 8.112 27.833 ;
        RECT  5.292 2.151 5.412 27.833 ;
        RECT  2.592 2.151 2.712 27.833 ;
    END
  END VDD
  PIN VSS
    DIRECTION INOUT ;
    USE GROUND ;
    PORT
      LAYER M5 ;
        RECT  61.8 2.137 61.92 27.819 ;
        RECT  59.1 2.137 59.22 27.819 ;
        RECT  56.4 2.137 56.52 27.819 ;
        RECT  53.7 2.137 53.82 27.819 ;
        RECT  51 2.137 51.12 27.819 ;
        RECT  48.3 2.137 48.42 27.819 ;
        RECT  45.6 2.137 45.72 27.819 ;
        RECT  42.9 2.137 43.02 27.819 ;
        RECT  40.2 2.137 40.32 27.819 ;
        RECT  37.5 2.137 37.62 27.819 ;
        RECT  34.8 2.137 34.92 27.819 ;
        RECT  32.1 2.137 32.22 27.819 ;
        RECT  29.4 2.137 29.52 27.819 ;
        RECT  26.7 2.137 26.82 27.819 ;
        RECT  24 2.137 24.12 27.819 ;
        RECT  21.3 2.137 21.42 27.819 ;
        RECT  18.6 2.137 18.72 27.819 ;
        RECT  15.9 2.137 16.02 27.819 ;
        RECT  13.2 2.137 13.32 27.819 ;
        RECT  10.5 2.137 10.62 27.819 ;
        RECT  7.8 2.137 7.92 27.819 ;
        RECT  5.1 2.137 5.22 27.819 ;
        RECT  2.4 2.137 2.52 27.819 ;
    END
  END VSS
  OBS
    LAYER RVTN ;
     RECT  2.16 2.16 62.586 2.295 ;
     RECT  2.16 2.565 62.586 2.835 ;
     RECT  2.16 3.105 62.586 3.375 ;
     RECT  2.16 3.645 62.586 3.915 ;
     RECT  2.16 4.185 62.586 4.455 ;
     RECT  2.16 4.725 62.586 4.995 ;
     RECT  2.16 5.265 62.586 5.535 ;
     RECT  2.16 5.805 62.586 6.075 ;
     RECT  2.16 6.345 62.586 6.615 ;
     RECT  2.16 6.885 62.586 7.155 ;
     RECT  2.16 7.425 62.586 7.695 ;
     RECT  2.16 7.965 62.586 8.235 ;
     RECT  2.16 8.505 62.586 8.775 ;
     RECT  2.16 9.045 62.586 9.315 ;
     RECT  2.16 9.585 62.586 9.855 ;
     RECT  2.16 10.125 62.586 10.395 ;
     RECT  2.16 10.665 62.586 10.935 ;
     RECT  2.16 11.205 62.586 11.475 ;
     RECT  2.16 11.745 62.586 12.015 ;
     RECT  2.16 12.285 62.586 12.555 ;
     RECT  2.16 12.825 62.586 13.095 ;
     RECT  2.16 13.365 62.586 13.635 ;
     RECT  2.16 13.905 62.586 14.175 ;
     RECT  2.16 14.445 62.586 14.715 ;
     RECT  2.16 14.985 62.586 15.255 ;
     RECT  2.16 15.525 62.586 15.795 ;
     RECT  2.16 16.065 62.586 16.335 ;
     RECT  2.16 16.605 62.586 16.875 ;
     RECT  2.16 17.145 62.586 17.415 ;
     RECT  2.16 17.685 62.586 17.955 ;
     RECT  2.16 18.225 62.586 18.495 ;
     RECT  2.16 18.765 62.586 19.035 ;
     RECT  2.16 19.305 62.586 19.575 ;
     RECT  2.16 19.845 62.586 20.115 ;
     RECT  2.16 20.385 62.586 20.655 ;
     RECT  2.16 20.925 62.586 21.195 ;
     RECT  2.16 21.465 62.586 21.735 ;
     RECT  2.16 22.005 62.586 22.275 ;
     RECT  2.16 22.545 62.586 22.815 ;
     RECT  2.16 23.085 62.586 23.355 ;
     RECT  2.16 23.625 62.586 23.895 ;
     RECT  2.16 24.165 62.586 24.435 ;
     RECT  2.16 24.705 62.586 24.975 ;
     RECT  2.16 25.245 62.586 25.515 ;
     RECT  2.16 25.785 62.586 26.055 ;
     RECT  2.16 26.325 62.586 26.595 ;
     RECT  2.16 26.865 62.586 27.135 ;
     RECT  2.16 27.405 62.586 27.675 ;
    LAYER RVTP ;
     RECT  2.16 2.295 62.586 2.565 ;
     RECT  2.16 2.835 62.586 3.105 ;
     RECT  2.16 3.375 62.586 3.645 ;
     RECT  2.16 3.915 62.586 4.185 ;
     RECT  2.16 4.455 62.586 4.725 ;
     RECT  2.16 4.995 62.586 5.265 ;
     RECT  2.16 5.535 62.586 5.805 ;
     RECT  2.16 6.075 62.586 6.345 ;
     RECT  2.16 6.615 62.586 6.885 ;
     RECT  2.16 7.155 62.586 7.425 ;
     RECT  2.16 7.695 62.586 7.965 ;
     RECT  2.16 8.235 62.586 8.505 ;
     RECT  2.16 8.775 62.586 9.045 ;
     RECT  2.16 9.315 62.586 9.585 ;
     RECT  2.16 9.855 62.586 10.125 ;
     RECT  2.16 10.395 62.586 10.665 ;
     RECT  2.16 10.935 62.586 11.205 ;
     RECT  2.16 11.475 62.586 11.745 ;
     RECT  2.16 12.015 62.586 12.285 ;
     RECT  2.16 12.555 62.586 12.825 ;
     RECT  2.16 13.095 62.586 13.365 ;
     RECT  2.16 13.635 62.586 13.905 ;
     RECT  2.16 14.175 62.586 14.445 ;
     RECT  2.16 14.715 62.586 14.985 ;
     RECT  2.16 15.255 62.586 15.525 ;
     RECT  2.16 15.795 62.586 16.065 ;
     RECT  2.16 16.335 62.586 16.605 ;
     RECT  2.16 16.875 62.586 17.145 ;
     RECT  2.16 17.415 62.586 17.685 ;
     RECT  2.16 17.955 62.586 18.225 ;
     RECT  2.16 18.495 62.586 18.765 ;
     RECT  2.16 19.035 62.586 19.305 ;
     RECT  2.16 19.575 62.586 19.845 ;
     RECT  2.16 20.115 62.586 20.385 ;
     RECT  2.16 20.655 62.586 20.925 ;
     RECT  2.16 21.195 62.586 21.465 ;
     RECT  2.16 21.735 62.586 22.005 ;
     RECT  2.16 22.275 62.586 22.545 ;
     RECT  2.16 22.815 62.586 23.085 ;
     RECT  2.16 23.355 62.586 23.625 ;
     RECT  2.16 23.895 62.586 24.165 ;
     RECT  2.16 24.435 62.586 24.705 ;
     RECT  2.16 24.975 62.586 25.245 ;
     RECT  2.16 25.515 62.586 25.785 ;
     RECT  2.16 26.055 62.586 26.325 ;
     RECT  2.16 26.595 62.586 26.865 ;
     RECT  2.16 27.135 62.586 27.405 ;
     RECT  2.16 27.675 62.586 27.81 ;
    LAYER M1 ;
     RECT  2.16 2.151 62.586 27.819 ;
    LAYER M2 ;
     RECT  2.16 2.151 24.979 27.819 ;
     RECT  24.979 2.151 25.087 27.864 ;
     RECT  25.087 2.151 25.771 27.936 ;
     RECT  25.987 29.34 26.203 29.358 ;
     RECT  25.771 2.151 26.267 27.972 ;
     RECT  26.203 29.034 26.275 29.358 ;
     RECT  26.275 29.034 26.419 30.096 ;
     RECT  26.267 2.151 27.779 27.936 ;
     RECT  26.419 29.034 27.967 30.168 ;
     RECT  27.967 28.998 28.427 30.168 ;
     RECT  28.427 29.034 28.499 30.168 ;
     RECT  28.499 29.034 28.571 29.358 ;
     RECT  27.779 2.151 28.579 27.819 ;
     RECT  28.571 29.34 29.219 29.358 ;
     RECT  28.499 30.15 29.227 30.168 ;
     RECT  29.227 30.006 30.443 30.168 ;
     RECT  30.443 30.006 30.559 30.096 ;
     RECT  30.487 28.962 30.587 28.98 ;
     RECT  30.559 29.961 30.731 30.096 ;
     RECT  30.847 29.034 30.947 29.052 ;
     RECT  30.731 30.078 31.207 30.096 ;
     RECT  31.207 30.078 31.343 30.168 ;
     RECT  31.531 30.042 31.711 30.06 ;
     RECT  28.579 2.106 32.071 27.819 ;
     RECT  31.711 30.006 32.071 30.06 ;
     RECT  32.071 2.034 32.179 27.819 ;
     RECT  32.179 2.034 32.323 27.936 ;
     RECT  32.071 30.006 32.359 30.168 ;
     RECT  32.359 29.961 32.459 30.168 ;
     RECT  32.459 30.006 32.495 30.168 ;
     RECT  32.495 30.078 32.819 30.168 ;
     RECT  28.111 0.846 33.035 0.864 ;
     RECT  32.819 30.15 33.215 30.168 ;
     RECT  31.999 29.034 33.467 29.052 ;
     RECT  33.907 0.036 34.087 0.054 ;
     RECT  34.087 0.036 34.159 0.198 ;
     RECT  34.159 0.036 34.951 0.279 ;
     RECT  34.951 0.036 35.383 0.324 ;
     RECT  35.383 0.036 35.555 0.36 ;
     RECT  32.323 1.881 35.915 27.936 ;
     RECT  35.555 0.036 35.987 0.198 ;
     RECT  35.915 1.881 36.203 27.864 ;
     RECT  35.987 0.036 36.347 0.054 ;
     RECT  36.203 2.151 37.319 27.864 ;
     RECT  37.319 2.151 62.586 27.819 ;
    LAYER M3 ;
     RECT  33.948 0.012 36.198 0.031 ;
     RECT  29.016 0.043 29.034 0.091 ;
     RECT  30.78 0.043 30.798 0.091 ;
     RECT  33.912 0.031 36.342 0.091 ;
     RECT  29.016 0.091 29.322 0.139 ;
     RECT  30.204 0.091 31.266 0.139 ;
     RECT  32.58 0.091 32.598 0.139 ;
     RECT  33.588 0.091 36.342 0.139 ;
     RECT  32.58 0.139 36.342 0.283 ;
     RECT  37.332 0.091 37.35 0.283 ;
     RECT  29.016 0.139 31.734 0.523 ;
     RECT  32.58 0.283 37.35 0.523 ;
     RECT  38.088 0.091 38.286 0.523 ;
     RECT  28.116 0.841 28.134 2.101 ;
     RECT  29.016 0.523 38.286 2.101 ;
     RECT  26.064 1.723 26.082 2.143 ;
     RECT  26.064 2.143 26.805 2.219 ;
     RECT  26.715 2.219 26.805 2.263 ;
     RECT  28.116 2.101 38.286 2.263 ;
     RECT  2.415 2.143 2.505 2.413 ;
     RECT  5.115 2.143 5.205 2.413 ;
     RECT  7.815 2.143 7.905 2.413 ;
     RECT  10.515 2.143 10.605 2.413 ;
     RECT  13.215 2.143 13.305 2.413 ;
     RECT  15.915 2.143 16.005 2.413 ;
     RECT  18.615 2.143 18.705 2.413 ;
     RECT  21.315 2.143 21.405 2.413 ;
     RECT  24.015 2.143 24.105 2.413 ;
     RECT  40.215 2.143 40.305 2.413 ;
     RECT  42.915 2.143 43.005 2.413 ;
     RECT  45.615 2.143 45.705 2.413 ;
     RECT  48.315 2.143 48.405 2.413 ;
     RECT  51.015 2.143 51.105 2.413 ;
     RECT  53.715 2.143 53.805 2.413 ;
     RECT  56.415 2.143 56.505 2.413 ;
     RECT  59.115 2.143 59.205 2.413 ;
     RECT  61.815 2.143 61.905 2.413 ;
     RECT  26.715 2.263 38.286 3.451 ;
     RECT  26.316 3.451 38.286 3.569 ;
     RECT  26.316 3.569 27.054 3.577 ;
     RECT  26.172 3.577 27.054 3.605 ;
     RECT  26.172 3.605 26.997 3.629 ;
     RECT  26.715 3.629 26.997 12.361 ;
     RECT  28.116 3.569 38.286 13.981 ;
     RECT  44.352 14.071 44.37 14.179 ;
     RECT  44.352 14.179 44.658 14.251 ;
     RECT  44.136 14.251 44.658 14.413 ;
     RECT  44.1 14.413 44.658 14.449 ;
     RECT  60.984 14.251 61.002 14.449 ;
     RECT  61.815 2.413 62.097 14.449 ;
     RECT  42.915 2.413 43.197 14.485 ;
     RECT  44.1 14.449 44.73 14.485 ;
     RECT  42.915 14.485 44.73 14.549 ;
     RECT  60.984 14.449 62.097 14.639 ;
     RECT  61.128 14.639 62.097 14.909 ;
     RECT  61.815 14.909 62.097 15.019 ;
     RECT  61.815 15.019 62.91 15.245 ;
     RECT  26.715 12.361 27.198 15.331 ;
     RECT  27.972 13.981 38.286 15.331 ;
     RECT  61.815 15.245 62.154 15.341 ;
     RECT  26.715 15.331 38.286 20.587 ;
     RECT  26.715 20.587 38.754 20.683 ;
     RECT  26.715 20.683 39.186 20.717 ;
     RECT  39.168 20.717 39.186 20.723 ;
     RECT  40.215 2.413 40.497 20.725 ;
     RECT  39.492 20.725 40.497 20.765 ;
     RECT  26.715 20.717 38.286 21.199 ;
     RECT  25.992 21.199 38.286 21.659 ;
     RECT  25.992 21.659 38.178 23.549 ;
     RECT  42.915 14.549 43.614 23.657 ;
     RECT  25.992 23.549 38.106 24.359 ;
     RECT  25.2 25.003 25.218 25.439 ;
     RECT  25.992 24.359 37.797 25.819 ;
     RECT  25.056 25.591 25.074 26.203 ;
     RECT  25.884 25.819 37.797 26.203 ;
     RECT  25.056 26.203 37.797 26.237 ;
     RECT  24.015 2.413 24.297 27.445 ;
     RECT  25.344 26.237 37.797 27.445 ;
     RECT  2.415 2.413 2.697 27.557 ;
     RECT  5.115 2.413 5.397 27.557 ;
     RECT  7.815 2.413 8.097 27.557 ;
     RECT  10.515 2.413 10.797 27.557 ;
     RECT  13.215 2.413 13.497 27.557 ;
     RECT  15.915 2.413 16.197 27.557 ;
     RECT  18.615 2.413 18.897 27.557 ;
     RECT  21.315 2.413 21.597 27.557 ;
     RECT  24.015 27.445 37.797 27.557 ;
     RECT  40.215 20.765 40.497 27.557 ;
     RECT  42.915 23.657 43.197 27.557 ;
     RECT  45.615 2.413 45.897 27.557 ;
     RECT  48.315 2.413 48.597 27.557 ;
     RECT  51.015 2.413 51.297 27.557 ;
     RECT  53.715 2.413 53.997 27.557 ;
     RECT  56.415 2.413 56.697 27.557 ;
     RECT  59.115 2.413 59.397 27.557 ;
     RECT  61.815 15.341 62.097 27.557 ;
     RECT  24.207 27.557 37.797 27.635 ;
     RECT  2.607 27.557 2.697 27.827 ;
     RECT  5.307 27.557 5.397 27.827 ;
     RECT  8.007 27.557 8.097 27.827 ;
     RECT  10.707 27.557 10.797 27.827 ;
     RECT  13.407 27.557 13.497 27.827 ;
     RECT  16.107 27.557 16.197 27.827 ;
     RECT  18.807 27.557 18.897 27.827 ;
     RECT  21.507 27.557 21.597 27.827 ;
     RECT  24.207 27.635 36.558 27.827 ;
     RECT  37.296 27.635 37.797 27.827 ;
     RECT  40.407 27.557 40.497 27.827 ;
     RECT  43.107 27.557 43.197 27.827 ;
     RECT  45.807 27.557 45.897 27.827 ;
     RECT  48.507 27.557 48.597 27.827 ;
     RECT  51.207 27.557 51.297 27.827 ;
     RECT  53.907 27.557 53.997 27.827 ;
     RECT  56.607 27.557 56.697 27.827 ;
     RECT  59.307 27.557 59.397 27.827 ;
     RECT  62.007 27.557 62.097 27.827 ;
     RECT  24.984 27.827 34.506 27.869 ;
     RECT  37.296 27.827 37.314 27.869 ;
     RECT  25.092 27.869 34.506 27.917 ;
     RECT  25.092 27.917 33.462 27.941 ;
     RECT  35.316 27.827 36.558 27.941 ;
     RECT  36.54 27.941 36.558 28.205 ;
     RECT  35.316 27.941 35.442 28.253 ;
     RECT  35.316 28.253 35.334 28.301 ;
     RECT  34.452 27.917 34.506 28.493 ;
     RECT  25.668 27.941 33.462 28.781 ;
     RECT  25.92 28.781 33.462 28.829 ;
     RECT  25.992 28.829 33.462 29.057 ;
     RECT  25.992 29.057 33.21 29.363 ;
     RECT  34.488 28.493 34.506 29.645 ;
     RECT  26.064 29.363 33.21 30.125 ;
     RECT  26.244 30.125 33.21 30.173 ;
     RECT  26.244 30.173 33.102 30.204 ;
    LAYER M4 ;
     RECT  2.408 2.148 2.512 27.552 ;
     RECT  2.512 2.418 2.6 27.552 ;
     RECT  2.6 2.418 2.704 27.822 ;
     RECT  5.108 2.148 5.212 27.552 ;
     RECT  5.212 2.418 5.3 27.552 ;
     RECT  5.3 2.418 5.404 27.822 ;
     RECT  7.808 2.148 7.912 27.552 ;
     RECT  7.912 2.418 8 27.552 ;
     RECT  8 2.418 8.104 27.822 ;
     RECT  10.508 2.148 10.612 27.552 ;
     RECT  10.612 2.418 10.7 27.552 ;
     RECT  10.7 2.418 10.804 27.822 ;
     RECT  13.208 2.148 13.312 27.552 ;
     RECT  13.312 2.418 13.4 27.552 ;
     RECT  13.4 2.418 13.504 27.822 ;
     RECT  15.908 2.148 16.012 27.552 ;
     RECT  16.012 2.418 16.1 27.552 ;
     RECT  16.1 2.418 16.204 27.822 ;
     RECT  18.608 2.148 18.712 27.552 ;
     RECT  18.712 2.418 18.8 27.552 ;
     RECT  18.8 2.418 18.904 27.822 ;
     RECT  21.308 2.148 21.412 27.552 ;
     RECT  21.412 2.418 21.5 27.552 ;
     RECT  21.5 2.418 21.604 27.822 ;
     RECT  24.008 2.148 24.112 27.552 ;
     RECT  24.112 2.418 24.2 27.552 ;
     RECT  24.2 2.418 24.304 27.822 ;
     RECT  24.304 26.208 25.333 26.232 ;
     RECT  25.333 26.208 25.441 26.616 ;
     RECT  25.441 26.208 25.513 27.48 ;
     RECT  25.513 26.208 25.693 27.672 ;
     RECT  25.657 28.752 25.693 28.776 ;
     RECT  25.693 26.208 25.873 28.776 ;
     RECT  24.304 25.008 25.909 25.032 ;
     RECT  25.873 26.112 25.909 28.776 ;
     RECT  26.053 1.728 26.137 1.752 ;
     RECT  26.161 3.6 26.708 3.624 ;
     RECT  26.665 23.952 26.708 23.976 ;
     RECT  25.909 25.008 26.708 28.824 ;
     RECT  26.708 2.148 26.812 28.824 ;
     RECT  26.053 30.096 26.849 30.12 ;
     RECT  26.812 2.418 27.004 28.824 ;
     RECT  27.004 22.656 27.721 28.824 ;
     RECT  27.721 22.656 28.105 23.88 ;
     RECT  28.105 22.56 28.753 23.88 ;
     RECT  28.753 22.032 28.789 23.88 ;
     RECT  27.721 25.008 28.789 28.824 ;
     RECT  28.789 22.032 29.153 28.824 ;
     RECT  29.005 0.048 29.185 0.072 ;
     RECT  27.004 3.6 29.408 3.624 ;
     RECT  29.125 10.896 29.408 10.92 ;
     RECT  29.269 12 29.408 12.024 ;
     RECT  29.153 22.032 29.408 28.776 ;
     RECT  29.408 2.148 29.441 28.776 ;
     RECT  29.185 0.048 29.605 0.84 ;
     RECT  29.441 2.148 29.651 28.008 ;
     RECT  29.651 2.148 29.704 27.96 ;
     RECT  29.605 0.048 29.861 1.176 ;
     RECT  29.701 30.048 29.893 30.072 ;
     RECT  29.893 29.952 30.445 30.072 ;
     RECT  30.445 29.04 30.593 30.072 ;
     RECT  29.704 12 30.737 12.552 ;
     RECT  29.861 0.048 30.809 1.752 ;
     RECT  30.809 0.096 30.853 1.752 ;
     RECT  29.704 3.12 30.853 3.624 ;
     RECT  29.704 10.272 30.901 10.92 ;
     RECT  30.853 0.096 31.097 3.624 ;
     RECT  31.097 0.096 31.133 1.752 ;
     RECT  30.901 10.272 31.133 11.4 ;
     RECT  29.704 21.168 31.429 27.96 ;
     RECT  31.429 21.168 31.525 28.488 ;
     RECT  30.593 30 31.621 30.072 ;
     RECT  31.333 5.136 31.669 5.16 ;
     RECT  31.621 29.808 31.669 30.072 ;
     RECT  29.704 15.984 31.813 16.008 ;
     RECT  31.669 29.808 31.817 30.168 ;
     RECT  31.817 29.808 31.925 30.12 ;
     RECT  31.097 2.784 32.029 3.624 ;
     RECT  31.669 5.136 32.029 6.12 ;
     RECT  32.029 2.784 32.108 6.12 ;
     RECT  31.717 7.44 32.108 7.464 ;
     RECT  31.133 10.32 32.108 11.4 ;
     RECT  30.737 12.528 32.108 12.552 ;
     RECT  31.813 15.984 32.108 16.392 ;
     RECT  31.957 18.72 32.108 18.744 ;
     RECT  31.525 20.304 32.108 28.488 ;
     RECT  31.133 0.096 32.389 1.176 ;
     RECT  32.108 2.148 32.389 28.488 ;
     RECT  32.389 0.096 32.404 28.488 ;
     RECT  32.404 0.096 32.501 3.432 ;
     RECT  32.404 4.512 32.501 7.992 ;
     RECT  32.501 5.088 32.645 7.992 ;
     RECT  32.404 10.896 32.753 10.92 ;
     RECT  32.404 15.984 32.789 16.392 ;
     RECT  32.501 2.736 32.819 3.432 ;
     RECT  32.645 7.248 32.86 7.992 ;
     RECT  32.819 2.736 32.915 2.856 ;
     RECT  32.915 2.736 33.011 2.808 ;
     RECT  32.645 5.088 33.052 6.264 ;
     RECT  33.052 5.088 33.107 6.12 ;
     RECT  32.789 16.368 33.221 16.392 ;
     RECT  32.86 7.392 33.299 7.992 ;
     RECT  32.404 18.72 33.397 18.744 ;
     RECT  32.404 20.304 33.397 28.488 ;
     RECT  33.107 6 33.509 6.12 ;
     RECT  33.613 13.056 33.697 13.08 ;
     RECT  32.501 0.096 33.973 1.176 ;
     RECT  33.011 2.736 34.189 2.76 ;
     RECT  33.509 6.096 34.213 6.12 ;
     RECT  33.299 7.392 34.213 7.416 ;
     RECT  33.397 18.72 34.481 28.488 ;
     RECT  32.101 29.616 34.517 29.64 ;
     RECT  33.973 0.048 34.549 1.176 ;
     RECT  34.189 2.304 34.549 2.856 ;
     RECT  34.549 0.048 34.808 2.856 ;
     RECT  34.297 3.936 34.808 3.96 ;
     RECT  34.213 6.096 34.808 7.416 ;
     RECT  33.901 14.832 34.808 14.856 ;
     RECT  34.621 16.8 34.808 16.824 ;
     RECT  34.481 18.72 34.808 28.296 ;
     RECT  34.808 0.048 35.104 28.296 ;
     RECT  35.104 6.096 35.267 6.12 ;
     RECT  35.104 21.792 35.345 28.296 ;
     RECT  35.104 18.72 35.363 20.76 ;
     RECT  35.363 18.912 35.381 20.76 ;
     RECT  35.345 21.792 35.453 28.248 ;
     RECT  35.104 0.048 35.489 2.28 ;
     RECT  35.489 0.288 35.699 2.28 ;
     RECT  35.453 21.792 35.705 28.2 ;
     RECT  35.705 21.792 35.849 24.888 ;
     RECT  35.699 0.336 35.891 2.28 ;
     RECT  35.891 0.432 35.993 2.28 ;
     RECT  35.993 0.432 36.029 0.888 ;
     RECT  35.849 21.792 36.131 22.584 ;
     RECT  35.104 16.8 36.179 16.824 ;
     RECT  35.381 19.344 36.281 20.76 ;
     RECT  35.705 25.968 36.323 28.2 ;
     RECT  35.849 24.192 36.353 24.888 ;
     RECT  36.323 25.968 36.353 27.192 ;
     RECT  35.104 4.512 36.371 4.536 ;
     RECT  36.353 25.968 36.425 27.096 ;
     RECT  36.205 6.24 36.467 6.264 ;
     RECT  35.993 2.256 36.476 2.28 ;
     RECT  36.425 25.968 36.533 25.992 ;
     RECT  36.425 27.072 36.533 27.096 ;
     RECT  36.323 28.176 36.569 28.2 ;
     RECT  36.281 19.584 36.661 20.76 ;
     RECT  36.131 21.792 36.661 21.816 ;
     RECT  36.029 0.432 36.925 0.552 ;
     RECT  36.421 15.216 36.997 15.24 ;
     RECT  36.925 0.288 37.277 0.552 ;
     RECT  36.476 2.256 37.381 2.856 ;
     RECT  37.381 2.016 37.508 2.856 ;
     RECT  36.229 14.112 37.508 14.136 ;
     RECT  36.997 15.216 37.508 15.336 ;
     RECT  36.661 19.584 37.508 21.816 ;
     RECT  36.353 24.192 37.508 24.456 ;
     RECT  37.508 2.016 37.619 27.552 ;
     RECT  37.619 2.418 37.7 27.552 ;
     RECT  37.7 2.418 37.804 27.822 ;
     RECT  37.277 0.096 37.933 0.552 ;
     RECT  37.933 0.096 38.017 0.6 ;
     RECT  38.017 0.096 38.195 0.552 ;
     RECT  38.195 0.096 38.297 0.12 ;
     RECT  37.804 20.592 38.765 20.712 ;
     RECT  38.765 20.688 39.197 20.712 ;
     RECT  37.804 14.112 39.493 14.136 ;
     RECT  37.804 15.216 39.493 15.336 ;
     RECT  39.493 14.112 40.208 15.336 ;
     RECT  39.452 20.736 40.208 20.76 ;
     RECT  37.804 24.432 40.208 24.456 ;
     RECT  40.208 2.148 40.312 27.552 ;
     RECT  40.312 2.418 40.4 27.552 ;
     RECT  40.4 2.418 40.504 27.822 ;
     RECT  40.504 14.112 42.908 15.336 ;
     RECT  42.908 2.148 43.012 27.552 ;
     RECT  43.012 2.418 43.1 27.552 ;
     RECT  43.1 2.418 43.204 27.822 ;
     RECT  43.204 14.112 44.381 15.336 ;
     RECT  44.381 14.4 44.489 15.336 ;
     RECT  44.489 15.216 45.608 15.336 ;
     RECT  45.608 2.148 45.712 27.552 ;
     RECT  45.712 2.418 45.8 27.552 ;
     RECT  45.8 2.418 45.904 27.822 ;
     RECT  45.904 15.216 48.308 15.336 ;
     RECT  48.308 2.148 48.412 27.552 ;
     RECT  48.412 2.418 48.5 27.552 ;
     RECT  48.5 2.418 48.604 27.822 ;
     RECT  48.604 15.216 51.008 15.336 ;
     RECT  51.008 2.148 51.112 27.552 ;
     RECT  51.112 2.418 51.2 27.552 ;
     RECT  51.2 2.418 51.304 27.822 ;
     RECT  51.304 15.216 53.708 15.336 ;
     RECT  53.708 2.148 53.812 27.552 ;
     RECT  53.812 2.418 53.9 27.552 ;
     RECT  53.9 2.418 54.004 27.822 ;
     RECT  54.004 15.216 56.408 15.336 ;
     RECT  56.408 2.148 56.512 27.552 ;
     RECT  56.512 2.418 56.6 27.552 ;
     RECT  56.6 2.418 56.704 27.822 ;
     RECT  56.704 15.216 59.108 15.336 ;
     RECT  59.108 2.148 59.212 27.552 ;
     RECT  59.212 2.418 59.3 27.552 ;
     RECT  59.3 2.418 59.404 27.822 ;
     RECT  59.404 15.216 61.808 15.336 ;
     RECT  61.808 2.148 61.912 27.552 ;
     RECT  61.912 2.418 62 27.552 ;
     RECT  62 2.418 62.104 27.822 ;
     RECT  62.104 15.024 62.921 15.336 ;
     RECT  62.921 15.12 64.716 15.336 ;
    LAYER M5 ;
     RECT  29.136 0.016 38.28 0.131 ;
     RECT  29.136 0.131 38.184 0.563 ;
     RECT  29.136 0.563 37.992 0.611 ;
     RECT  26.064 0.016 26.088 1.763 ;
     RECT  29.136 0.611 37.608 2.137 ;
     RECT  2.4 2.137 2.52 2.151 ;
     RECT  5.1 2.137 5.22 2.151 ;
     RECT  7.8 2.137 7.92 2.151 ;
     RECT  10.5 2.137 10.62 2.151 ;
     RECT  13.2 2.137 13.32 2.151 ;
     RECT  15.9 2.137 16.02 2.151 ;
     RECT  18.6 2.137 18.72 2.151 ;
     RECT  21.3 2.137 21.42 2.151 ;
     RECT  24 2.137 24.12 2.151 ;
     RECT  26.7 2.137 26.82 2.151 ;
     RECT  29.136 2.137 37.62 2.151 ;
     RECT  40.2 2.137 40.32 2.151 ;
     RECT  42.9 2.137 43.02 2.151 ;
     RECT  45.6 2.137 45.72 2.151 ;
     RECT  48.3 2.137 48.42 2.151 ;
     RECT  51 2.137 51.12 2.151 ;
     RECT  53.7 2.137 53.82 2.151 ;
     RECT  56.4 2.137 56.52 2.151 ;
     RECT  59.1 2.137 59.22 2.151 ;
     RECT  61.8 2.137 61.92 2.151 ;
     RECT  29.136 2.151 37.812 2.867 ;
     RECT  29.136 2.867 36.456 6.275 ;
     RECT  29.136 6.275 36.168 10.931 ;
     RECT  29.28 10.931 36.168 12.035 ;
     RECT  29.4 12.035 36.168 14.101 ;
     RECT  40.2 2.151 40.512 14.389 ;
     RECT  29.4 14.101 36.264 15.205 ;
     RECT  29.4 15.205 36.456 15.301 ;
     RECT  37.5 2.867 37.812 15.301 ;
     RECT  29.4 15.301 37.812 20.003 ;
     RECT  29.4 20.003 36.456 20.965 ;
     RECT  37.5 20.003 37.812 20.965 ;
     RECT  29.4 20.965 37.812 21.155 ;
     RECT  34.704 21.155 37.812 21.827 ;
     RECT  34.704 21.827 36.12 22.595 ;
     RECT  26.7 2.151 27.012 22.645 ;
     RECT  34.704 22.595 35.832 23.315 ;
     RECT  34.8 23.315 35.832 23.411 ;
     RECT  26.7 22.645 27.336 23.699 ;
     RECT  29.4 21.155 33.672 24.229 ;
     RECT  39.504 14.389 40.512 24.467 ;
     RECT  26.7 23.699 27.012 24.805 ;
     RECT  28.32 23.317 28.344 24.805 ;
     RECT  34.8 23.411 35.304 24.899 ;
     RECT  26.7 24.805 28.344 25.045 ;
     RECT  29.4 24.229 33.72 25.045 ;
     RECT  26.7 25.045 33.72 25.715 ;
     RECT  28.32 25.715 33.72 25.955 ;
     RECT  34.8 24.899 35.208 25.957 ;
     RECT  34.8 25.957 36.024 26.531 ;
     RECT  29.4 25.955 33.72 26.867 ;
     RECT  28.32 25.955 28.344 27.059 ;
     RECT  29.4 26.867 33.144 27.395 ;
     RECT  36.288 26.773 36.312 27.587 ;
     RECT  2.4 2.151 2.712 27.819 ;
     RECT  5.1 2.151 5.412 27.819 ;
     RECT  7.8 2.151 8.112 27.819 ;
     RECT  10.5 2.151 10.812 27.819 ;
     RECT  13.2 2.151 13.512 27.819 ;
     RECT  15.9 2.151 16.212 27.819 ;
     RECT  18.6 2.151 18.912 27.819 ;
     RECT  21.3 2.151 21.612 27.819 ;
     RECT  24 2.151 24.312 27.819 ;
     RECT  26.7 25.715 27.012 27.819 ;
     RECT  29.4 27.395 32.52 27.819 ;
     RECT  34.8 26.531 35.112 27.819 ;
     RECT  37.5 21.827 37.812 27.819 ;
     RECT  40.2 24.467 40.512 27.819 ;
     RECT  42.9 2.151 43.212 27.819 ;
     RECT  45.6 2.151 45.912 27.819 ;
     RECT  48.3 2.151 48.612 27.819 ;
     RECT  51 2.151 51.312 27.819 ;
     RECT  53.7 2.151 54.012 27.819 ;
     RECT  56.4 2.151 56.712 27.819 ;
     RECT  59.1 2.151 59.412 27.819 ;
     RECT  61.8 2.151 62.112 27.819 ;
     RECT  2.592 27.819 2.712 27.833 ;
     RECT  5.292 27.819 5.412 27.833 ;
     RECT  7.992 27.819 8.112 27.833 ;
     RECT  10.692 27.819 10.812 27.833 ;
     RECT  13.392 27.819 13.512 27.833 ;
     RECT  16.092 27.819 16.212 27.833 ;
     RECT  18.792 27.819 18.912 27.833 ;
     RECT  21.492 27.819 21.612 27.833 ;
     RECT  24.192 27.819 24.312 27.833 ;
     RECT  26.892 27.819 27.012 27.833 ;
     RECT  34.992 27.819 35.112 27.833 ;
     RECT  37.692 27.819 37.812 27.833 ;
     RECT  40.392 27.819 40.512 27.833 ;
     RECT  43.092 27.819 43.212 27.833 ;
     RECT  45.792 27.819 45.912 27.833 ;
     RECT  48.492 27.819 48.612 27.833 ;
     RECT  51.192 27.819 51.312 27.833 ;
     RECT  53.892 27.819 54.012 27.833 ;
     RECT  56.592 27.819 56.712 27.833 ;
     RECT  59.292 27.819 59.412 27.833 ;
     RECT  61.992 27.819 62.112 27.833 ;
     RECT  29.52 27.819 32.52 30.16 ;
  END
END qfd_rlyh0_128_NS_65x30
END LIBRARY
